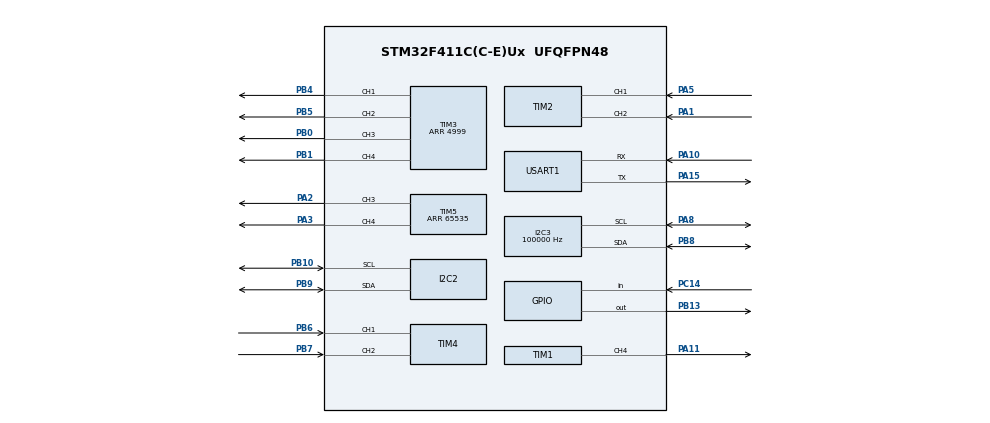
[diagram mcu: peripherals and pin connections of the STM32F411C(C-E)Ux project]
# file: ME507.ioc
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I2C3.ClockSpeed=100000
I2C3.I2C_Mode=I2C_Standard
Mcu.Family=STM32F4
Mcu.Name=STM32F411C(C-E)Ux
Mcu.Package=UFQFPN48
NVIC.PriorityGroup=NVIC_PRIORITYGROUP_4
NVIC.USART1_IRQn=true\:0\:0\:false\:false\:true\:true\:true\:true
PA0-WKUP.Mode=SYS_WakeUp0
PA0-WKUP.Signal=SYS_WKUP
PA1.Signal=S_TIM2_CH2
PA10.Mode=Asynchronous
PA10.Signal=USART1_RX
PA11.Signal=S_TIM1_CH4
PA13.Mode=Trace_Asynchronous_SW
PA13.Signal=SYS_JTMS-SWDIO
PA14.Mode=Trace_Asynchronous_SW
PA14.Signal=SYS_JTCK-SWCLK
PA15.Mode=Asynchronous
PA15.Signal=USART1_TX
PA2.Signal=S_TIM5_CH3
PA3.Signal=S_TIM5_CH4
PA5.Signal=S_TIM2_CH1_ETR
PA8.Mode=I2C
PA8.Signal=I2C3_SCL
PB0.Signal=S_TIM3_CH3
PB1.Signal=S_TIM3_CH4
PB10.Mode=I2C
PB10.Signal=I2C2_SCL
PB13.Signal=GPIO_Output
PB3.Mode=Trace_Asynchronous_SW
PB3.Signal=SYS_JTDO-SWO
PB4.Signal=S_TIM3_CH1
PB5.Signal=S_TIM3_CH2
PB6.Signal=S_TIM4_CH1
PB7.Signal=S_TIM4_CH2
PB8.Mode=I2C
PB8.Signal=I2C3_SDA
PB9.Mode=I2C
PB9.Signal=I2C2_SDA
PC14-OSC32_IN.Signal=GPIO_Input
PH0\ -\ OSC_IN.Mode=HSE-External-Oscillator
PH0\ -\ OSC_IN.Signal=RCC_OSC_IN
PH1\ -\ OSC_OUT.Mode=HSE-External-Oscillator
PH1\ -\ OSC_OUT.Signal=RCC_OSC_OUT
ProjectManager.HeapSize=0x200
ProjectManager.StackSize=0x400
ProjectManager.TargetToolchain=STM32CubeIDE
RCC.48MHZClocksFreq_Value=50000000
RCC.AHBFreq_Value=100000000
RCC.APB1CLKDivider=RCC_HCLK_DIV2
RCC.APB1Freq_Value=50000000
RCC.APB1TimFreq_Value=100000000
RCC.APB2Freq_Value=100000000
RCC.APB2TimFreq_Value=100000000
RCC.CortexFreq_Value=100000000
RCC.HCLKFreq_Value=100000000
RCC.HSE_VALUE=16000000
RCC.HSI_VALUE=16000000
RCC.LSE_VALUE=32768
RCC.PLLM=8
RCC.PLLN=100
RCC.SYSCLKFreq_VALUE=100000000
RCC.SYSCLKSource=RCC_SYSCLKSOURCE_PLLCLK
RCC.VCOOutputFreq_Value=200000000
SH.S_TIM1_CH4.0=TIM1_CH4,PWM Generation4 CH4
SH.S_TIM2_CH1_ETR.0=TIM2_CH1,Encoder_Interface
SH.S_TIM2_CH2.0=TIM2_CH2,Encoder_Interface
SH.S_TIM3_CH1.0=TIM3_CH1,PWM Generation1 CH1
SH.S_TIM3_CH2.0=TIM3_CH2,PWM Generation2 CH2
SH.S_TIM3_CH3.0=TIM3_CH3,PWM Generation3 CH3
SH.S_TIM3_CH4.0=TIM3_CH4,PWM Generation4 CH4
SH.S_TIM4_CH1.0=TIM4_CH1,Encoder_Interface
SH.S_TIM4_CH2.0=TIM4_CH2,Encoder_Interface
SH.S_TIM5_CH3.0=TIM5_CH3,PWM Generation3 CH3
SH.S_TIM5_CH4.0=TIM5_CH4,PWM Generation4 CH4
TIM1.Channel-PWM\ Generation4\ CH4=TIM_CHANNEL_4
TIM1.Period=65535
TIM1.Prescaler=28
TIM3.Channel-PWM\ Generation1\ CH1=TIM_CHANNEL_1
TIM3.Channel-PWM\ Generation2\ CH2=TIM_CHANNEL_2
TIM3.Channel-PWM\ Generation3\ CH3=TIM_CHANNEL_3
TIM3.Channel-PWM\ Generation4\ CH4=TIM_CHANNEL_4
TIM3.Period=4999
TIM5.Channel-PWM\ Generation3\ CH3=TIM_CHANNEL_3
TIM5.Channel-PWM\ Generation4\ CH4=TIM_CHANNEL_4
TIM5.Period=65535
USART1.VirtualMode=VM_ASYNC
board=custom

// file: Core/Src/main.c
/* USER CODE BEGIN Header */
/**
  ******************************************************************************
  * @file           : main.c
  * @brief          : Main program body
  ******************************************************************************
  * @attention
  *
  * Copyright (c) 2025 STMicroelectronics.
  * All rights reserved.
  *
  * This software is licensed under terms that can be found in the LICENSE file
  * in the root directory of this software component.
  * If no LICENSE file comes with this software, it is provided AS-IS.
  *
  ******************************************************************************
  */
/* USER CODE END Header */
#include "main.h"

I2C_HandleTypeDef hi2c2;
I2C_HandleTypeDef hi2c3;

TIM_HandleTypeDef htim1;
TIM_HandleTypeDef htim2;
TIM_HandleTypeDef htim3;
TIM_HandleTypeDef htim4;
TIM_HandleTypeDef htim5;

UART_HandleTypeDef huart1;

void SystemClock_Config(void);
static void MX_GPIO_Init(void);
static void MX_USART1_UART_Init(void);
static void MX_TIM2_Init(void);
static void MX_I2C3_Init(void);
static void MX_TIM1_Init(void);
static void MX_TIM3_Init(void);
static void MX_TIM4_Init(void);
static void MX_TIM5_Init(void);
static void MX_I2C2_Init(void);

int main(void)
{

  /* MCU Configuration--------------------------------------------------------*/

  /* Reset of all peripherals, Initializes the Flash interface and the Systick. */
  HAL_Init();

  /* Configure the system clock */
  SystemClock_Config();

  /* Initialize all configured peripherals */
  MX_GPIO_Init();
  MX_USART1_UART_Init();
  MX_TIM2_Init();
  MX_I2C3_Init();
  MX_TIM1_Init();
  MX_TIM3_Init();
  MX_TIM4_Init();
  MX_TIM5_Init();
  MX_I2C2_Init();

  /* Infinite loop */
  while (1)
  {

  }
}

void SystemClock_Config(void)
{
  RCC_OscInitTypeDef RCC_OscInitStruct = {0};
  RCC_ClkInitTypeDef RCC_ClkInitStruct = {0};

  /** Configure the main internal regulator output voltage
  */
  __HAL_RCC_PWR_CLK_ENABLE();
  __HAL_PWR_VOLTAGESCALING_CONFIG(PWR_REGULATOR_VOLTAGE_SCALE1);

  /** Initializes the RCC Oscillators according to the specified parameters
  * in the RCC_OscInitTypeDef structure.
  */
  RCC_OscInitStruct.OscillatorType = RCC_OSCILLATORTYPE_HSI;
  RCC_OscInitStruct.HSIState = RCC_HSI_ON;
  RCC_OscInitStruct.HSICalibrationValue = RCC_HSICALIBRATION_DEFAULT;
  RCC_OscInitStruct.PLL.PLLState = RCC_PLL_ON;
  RCC_OscInitStruct.PLL.PLLSource = RCC_PLLSOURCE_HSI;
  RCC_OscInitStruct.PLL.PLLM = 8;
  RCC_OscInitStruct.PLL.PLLN = 96;
  RCC_OscInitStruct.PLL.PLLP = RCC_PLLP_DIV2;
  RCC_OscInitStruct.PLL.PLLQ = 4;
  if (HAL_RCC_OscConfig(&RCC_OscInitStruct) != HAL_OK)
  {
    Error_Handler();
  }

  /** Initializes the CPU, AHB and APB buses clocks
  */
  RCC_ClkInitStruct.ClockType = RCC_CLOCKTYPE_HCLK|RCC_CLOCKTYPE_SYSCLK
                              |RCC_CLOCKTYPE_PCLK1|RCC_CLOCKTYPE_PCLK2;
  RCC_ClkInitStruct.SYSCLKSource = RCC_SYSCLKSOURCE_PLLCLK;
  RCC_ClkInitStruct.AHBCLKDivider = RCC_SYSCLK_DIV1;
  RCC_ClkInitStruct.APB1CLKDivider = RCC_HCLK_DIV2;
  RCC_ClkInitStruct.APB2CLKDivider = RCC_HCLK_DIV1;

  if (HAL_RCC_ClockConfig(&RCC_ClkInitStruct, FLASH_LATENCY_3) != HAL_OK)
  {
    Error_Handler();
  }
}

static void MX_I2C2_Init(void)
{

  hi2c2.Instance = I2C2;
  hi2c2.Init.ClockSpeed = 100000;
  hi2c2.Init.DutyCycle = I2C_DUTYCYCLE_2;
  hi2c2.Init.OwnAddress1 = 0;
  hi2c2.Init.AddressingMode = I2C_ADDRESSINGMODE_7BIT;
  hi2c2.Init.DualAddressMode = I2C_DUALADDRESS_DISABLE;
  hi2c2.Init.OwnAddress2 = 0;
  hi2c2.Init.GeneralCallMode = I2C_GENERALCALL_DISABLE;
  hi2c2.Init.NoStretchMode = I2C_NOSTRETCH_DISABLE;
  if (HAL_I2C_Init(&hi2c2) != HAL_OK)
  {
    Error_Handler();
  }

}

static void MX_I2C3_Init(void)
{

  hi2c3.Instance = I2C3;
  hi2c3.Init.ClockSpeed = 100000;
  hi2c3.Init.DutyCycle = I2C_DUTYCYCLE_2;
  hi2c3.Init.OwnAddress1 = 0;
  hi2c3.Init.AddressingMode = I2C_ADDRESSINGMODE_7BIT;
  hi2c3.Init.DualAddressMode = I2C_DUALADDRESS_DISABLE;
  hi2c3.Init.OwnAddress2 = 0;
  hi2c3.Init.GeneralCallMode = I2C_GENERALCALL_DISABLE;
  hi2c3.Init.NoStretchMode = I2C_NOSTRETCH_DISABLE;
  if (HAL_I2C_Init(&hi2c3) != HAL_OK)
  {
    Error_Handler();
  }

}

static void MX_TIM1_Init(void)
{

  TIM_MasterConfigTypeDef sMasterConfig = {0};
  TIM_OC_InitTypeDef sConfigOC = {0};
  TIM_BreakDeadTimeConfigTypeDef sBreakDeadTimeConfig = {0};

  htim1.Instance = TIM1;
  htim1.Init.Prescaler = 0;
  htim1.Init.CounterMode = TIM_COUNTERMODE_UP;
  htim1.Init.Period = 4999;
  htim1.Init.ClockDivision = TIM_CLOCKDIVISION_DIV1;
  htim1.Init.RepetitionCounter = 0;
  htim1.Init.AutoReloadPreload = TIM_AUTORELOAD_PRELOAD_DISABLE;
  if (HAL_TIM_PWM_Init(&htim1) != HAL_OK)
  {
    Error_Handler();
  }
  sMasterConfig.MasterOutputTrigger = TIM_TRGO_RESET;
  sMasterConfig.MasterSlaveMode = TIM_MASTERSLAVEMODE_DISABLE;
  if (HAL_TIMEx_MasterConfigSynchronization(&htim1, &sMasterConfig) != HAL_OK)
  {
    Error_Handler();
  }
  sConfigOC.OCMode = TIM_OCMODE_PWM1;
  sConfigOC.Pulse = 0;
  sConfigOC.OCPolarity = TIM_OCPOLARITY_HIGH;
  sConfigOC.OCNPolarity = TIM_OCNPOLARITY_HIGH;
  sConfigOC.OCFastMode = TIM_OCFAST_DISABLE;
  sConfigOC.OCIdleState = TIM_OCIDLESTATE_RESET;
  sConfigOC.OCNIdleState = TIM_OCNIDLESTATE_RESET;
  if (HAL_TIM_PWM_ConfigChannel(&htim1, &sConfigOC, TIM_CHANNEL_2) != HAL_OK)
  {
    Error_Handler();
  }
  if (HAL_TIM_PWM_ConfigChannel(&htim1, &sConfigOC, TIM_CHANNEL_4) != HAL_OK)
  {
    Error_Handler();
  }
  sBreakDeadTimeConfig.OffStateRunMode = TIM_OSSR_DISABLE;
  sBreakDeadTimeConfig.OffStateIDLEMode = TIM_OSSI_DISABLE;
  sBreakDeadTimeConfig.LockLevel = TIM_LOCKLEVEL_OFF;
  sBreakDeadTimeConfig.DeadTime = 0;
  sBreakDeadTimeConfig.BreakState = TIM_BREAK_DISABLE;
  sBreakDeadTimeConfig.BreakPolarity = TIM_BREAKPOLARITY_HIGH;
  sBreakDeadTimeConfig.AutomaticOutput = TIM_AUTOMATICOUTPUT_DISABLE;
  if (HAL_TIMEx_ConfigBreakDeadTime(&htim1, &sBreakDeadTimeConfig) != HAL_OK)
  {
    Error_Handler();
  }
  HAL_TIM_MspPostInit(&htim1);

}

static void MX_TIM2_Init(void)
{

  TIM_Encoder_InitTypeDef sConfig = {0};
  TIM_MasterConfigTypeDef sMasterConfig = {0};

  htim2.Instance = TIM2;
  htim2.Init.Prescaler = 0;
  htim2.Init.CounterMode = TIM_COUNTERMODE_UP;
  htim2.Init.Period = 4294967295;
  htim2.Init.ClockDivision = TIM_CLOCKDIVISION_DIV1;
  htim2.Init.AutoReloadPreload = TIM_AUTORELOAD_PRELOAD_DISABLE;
  sConfig.EncoderMode = TIM_ENCODERMODE_TI1;
  sConfig.IC1Polarity = TIM_ICPOLARITY_RISING;
  sConfig.IC1Selection = TIM_ICSELECTION_DIRECTTI;
  sConfig.IC1Prescaler = TIM_ICPSC_DIV1;
  sConfig.IC1Filter = 0;
  sConfig.IC2Polarity = TIM_ICPOLARITY_RISING;
  sConfig.IC2Selection = TIM_ICSELECTION_DIRECTTI;
  sConfig.IC2Prescaler = TIM_ICPSC_DIV1;
  sConfig.IC2Filter = 0;
  if (HAL_TIM_Encoder_Init(&htim2, &sConfig) != HAL_OK)
  {
    Error_Handler();
  }
  sMasterConfig.MasterOutputTrigger = TIM_TRGO_RESET;
  sMasterConfig.MasterSlaveMode = TIM_MASTERSLAVEMODE_DISABLE;
  if (HAL_TIMEx_MasterConfigSynchronization(&htim2, &sMasterConfig) != HAL_OK)
  {
    Error_Handler();
  }

}

static void MX_TIM3_Init(void)
{

  TIM_MasterConfigTypeDef sMasterConfig = {0};
  TIM_OC_InitTypeDef sConfigOC = {0};

  htim3.Instance = TIM3;
  htim3.Init.Prescaler = 0;
  htim3.Init.CounterMode = TIM_COUNTERMODE_UP;
  htim3.Init.Period = 65535;
  htim3.Init.ClockDivision = TIM_CLOCKDIVISION_DIV1;
  htim3.Init.AutoReloadPreload = TIM_AUTORELOAD_PRELOAD_DISABLE;
  if (HAL_TIM_PWM_Init(&htim3) != HAL_OK)
  {
    Error_Handler();
  }
  sMasterConfig.MasterOutputTrigger = TIM_TRGO_RESET;
  sMasterConfig.MasterSlaveMode = TIM_MASTERSLAVEMODE_DISABLE;
  if (HAL_TIMEx_MasterConfigSynchronization(&htim3, &sMasterConfig) != HAL_OK)
  {
    Error_Handler();
  }
  sConfigOC.OCMode = TIM_OCMODE_PWM1;
  sConfigOC.Pulse = 0;
  sConfigOC.OCPolarity = TIM_OCPOLARITY_HIGH;
  sConfigOC.OCFastMode = TIM_OCFAST_DISABLE;
  if (HAL_TIM_PWM_ConfigChannel(&htim3, &sConfigOC, TIM_CHANNEL_1) != HAL_OK)
  {
    Error_Handler();
  }
  if (HAL_TIM_PWM_ConfigChannel(&htim3, &sConfigOC, TIM_CHANNEL_2) != HAL_OK)
  {
    Error_Handler();
  }
  if (HAL_TIM_PWM_ConfigChannel(&htim3, &sConfigOC, TIM_CHANNEL_3) != HAL_OK)
  {
    Error_Handler();
  }
  if (HAL_TIM_PWM_ConfigChannel(&htim3, &sConfigOC, TIM_CHANNEL_4) != HAL_OK)
  {
    Error_Handler();
  }
  HAL_TIM_MspPostInit(&htim3);

}

static void MX_TIM4_Init(void)
{

  TIM_Encoder_InitTypeDef sConfig = {0};
  TIM_MasterConfigTypeDef sMasterConfig = {0};

  htim4.Instance = TIM4;
  htim4.Init.Prescaler = 0;
  htim4.Init.CounterMode = TIM_COUNTERMODE_UP;
  htim4.Init.Period = 65535;
  htim4.Init.ClockDivision = TIM_CLOCKDIVISION_DIV1;
  htim4.Init.AutoReloadPreload = TIM_AUTORELOAD_PRELOAD_DISABLE;
  sConfig.EncoderMode = TIM_ENCODERMODE_TI1;
  sConfig.IC1Polarity = TIM_ICPOLARITY_RISING;
  sConfig.IC1Selection = TIM_ICSELECTION_DIRECTTI;
  sConfig.IC1Prescaler = TIM_ICPSC_DIV1;
  sConfig.IC1Filter = 0;
  sConfig.IC2Polarity = TIM_ICPOLARITY_RISING;
  sConfig.IC2Selection = TIM_ICSELECTION_DIRECTTI;
  sConfig.IC2Prescaler = TIM_ICPSC_DIV1;
  sConfig.IC2Filter = 0;
  if (HAL_TIM_Encoder_Init(&htim4, &sConfig) != HAL_OK)
  {
    Error_Handler();
  }
  sMasterConfig.MasterOutputTrigger = TIM_TRGO_RESET;
  sMasterConfig.MasterSlaveMode = TIM_MASTERSLAVEMODE_DISABLE;
  if (HAL_TIMEx_MasterConfigSynchronization(&htim4, &sMasterConfig) != HAL_OK)
  {
    Error_Handler();
  }

}

static void MX_TIM5_Init(void)
{

  TIM_MasterConfigTypeDef sMasterConfig = {0};
  TIM_OC_InitTypeDef sConfigOC = {0};

  htim5.Instance = TIM5;
  htim5.Init.Prescaler = 0;
  htim5.Init.CounterMode = TIM_COUNTERMODE_UP;
  htim5.Init.Period = 65535;
  htim5.Init.ClockDivision = TIM_CLOCKDIVISION_DIV1;
  htim5.Init.AutoReloadPreload = TIM_AUTORELOAD_PRELOAD_DISABLE;
  if (HAL_TIM_PWM_Init(&htim5) != HAL_OK)
  {
    Error_Handler();
  }
  sMasterConfig.MasterOutputTrigger = TIM_TRGO_RESET;
  sMasterConfig.MasterSlaveMode = TIM_MASTERSLAVEMODE_DISABLE;
  if (HAL_TIMEx_MasterConfigSynchronization(&htim5, &sMasterConfig) != HAL_OK)
  {
    Error_Handler();
  }
  sConfigOC.OCMode = TIM_OCMODE_PWM1;
  sConfigOC.Pulse = 0;
  sConfigOC.OCPolarity = TIM_OCPOLARITY_HIGH;
  sConfigOC.OCFastMode = TIM_OCFAST_DISABLE;
  if (HAL_TIM_PWM_ConfigChannel(&htim5, &sConfigOC, TIM_CHANNEL_3) != HAL_OK)
  {
    Error_Handler();
  }
  if (HAL_TIM_PWM_ConfigChannel(&htim5, &sConfigOC, TIM_CHANNEL_4) != HAL_OK)
  {
    Error_Handler();
  }
  HAL_TIM_MspPostInit(&htim5);

}

static void MX_USART1_UART_Init(void)
{

  huart1.Instance = USART1;
  huart1.Init.BaudRate = 115200;
  huart1.Init.WordLength = UART_WORDLENGTH_8B;
  huart1.Init.StopBits = UART_STOPBITS_1;
  huart1.Init.Parity = UART_PARITY_NONE;
  huart1.Init.Mode = UART_MODE_TX_RX;
  huart1.Init.HwFlowCtl = UART_HWCONTROL_NONE;
  huart1.Init.OverSampling = UART_OVERSAMPLING_16;
  if (HAL_UART_Init(&huart1) != HAL_OK)
  {
    Error_Handler();
  }

}

static void MX_GPIO_Init(void)
{
  GPIO_InitTypeDef GPIO_InitStruct = {0};

  /* GPIO Ports Clock Enable */
  __HAL_RCC_GPIOC_CLK_ENABLE();
  __HAL_RCC_GPIOH_CLK_ENABLE();
  __HAL_RCC_GPIOA_CLK_ENABLE();
  __HAL_RCC_GPIOB_CLK_ENABLE();

  /*Configure GPIO pin Output Level */
  HAL_GPIO_WritePin(GPIOB, GPIO_PIN_13, GPIO_PIN_RESET);

  /*Configure GPIO pin : PC14 */
  GPIO_InitStruct.Pin = GPIO_PIN_14;
  GPIO_InitStruct.Mode = GPIO_MODE_INPUT;
  GPIO_InitStruct.Pull = GPIO_NOPULL;
  HAL_GPIO_Init(GPIOC, &GPIO_InitStruct);

  /*Configure GPIO pin : PB13 */
  GPIO_InitStruct.Pin = GPIO_PIN_13;
  GPIO_InitStruct.Mode = GPIO_MODE_OUTPUT_PP;
  GPIO_InitStruct.Pull = GPIO_NOPULL;
  GPIO_InitStruct.Speed = GPIO_SPEED_FREQ_LOW;
  HAL_GPIO_Init(GPIOB, &GPIO_InitStruct);

}

void Error_Handler(void)
{
  __disable_irq();
  while (1)
  {
  }
}
